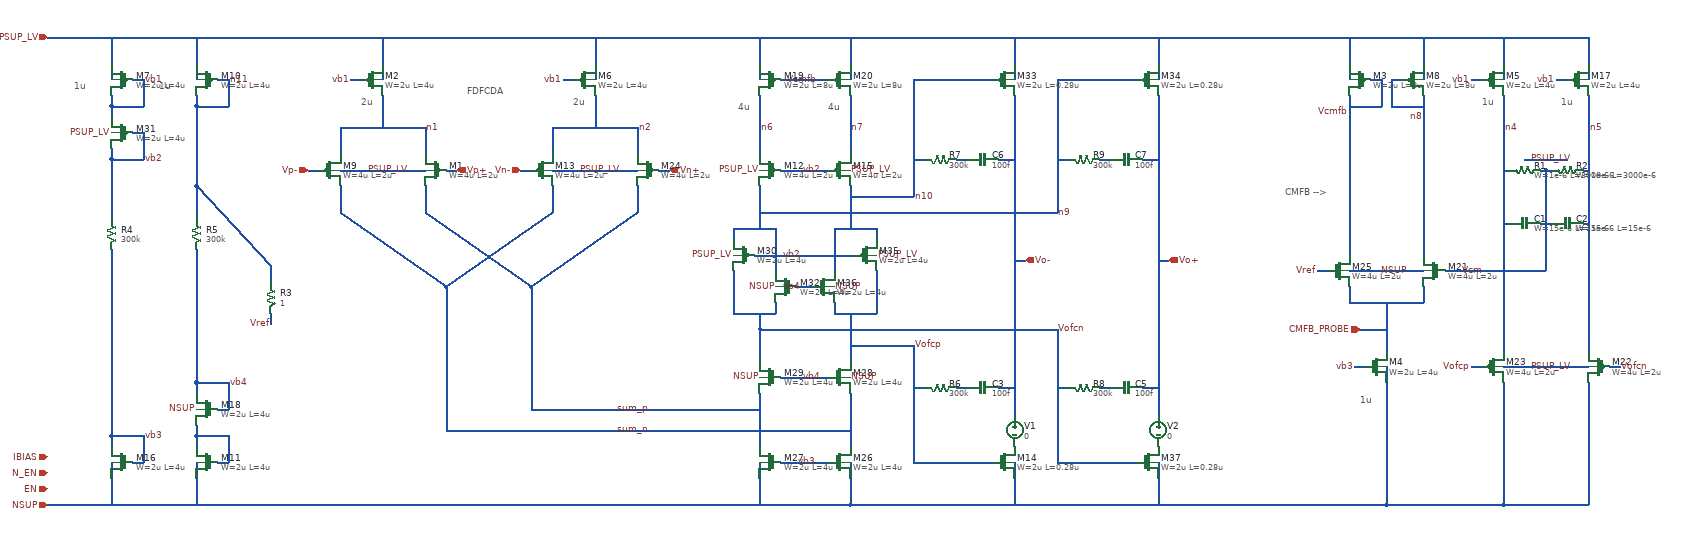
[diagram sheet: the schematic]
v {xschem version=3.4.7 file_version=1.2}
G {}
K {}
V {}
S {}
E {}
T {1u} -620 -650 0 0 0.4 0.4 {}
T {2u} -80 -620 0 0 0.4 0.4 {}
T {2u} 320 -620 0 0 0.4 0.4 {}
T {CMFB -->} 1660 -450 0 0 0.4 0.4 {}
T {4u} 630 -610 0 0 0.4 0.4 {}
T {4u} 800 -610 0 0 0.4 0.4 {}
T {1u} 1800 -60 0 0 0.4 0.4 {}
T {FDFCDA} 120 -640 0 0 0.4 0.4 {}
T {1u} 2030 -620 0 0 0.4 0.4 {}
T {1u} 2180 -620 0 0 0.4 0.4 {}
T {1u} -460 -650 0 0 0.4 0.4 {}
N -660 -730 -260 -730 {lab=PSUP_LV}
N -670 -730 -660 -730 {lab=PSUP_LV}
N -550 -680 -550 -650 {lab=PSUP_LV}
N -550 -730 -550 -680 {lab=PSUP_LV}
N -550 -600 -490 -600 {lab=vb1}
N -490 20 -490 70 {lab=vb3}
N -550 20 -550 40 {lab=vb3}
N -510 70 -490 70 {lab=vb3}
N -670 150 -230 150 {lab=NSUP}
N -120 -560 -120 -510 {lab=n1}
N 40 -560 40 -510 {lab=n1}
N -40 -620 -40 -560 {lab=n1}
N -40 -730 -40 -680 {lab=PSUP_LV}
N -120 -450 -120 -400 {lab=sum_n}
N 360 -680 360 -650 {lab=PSUP_LV}
N -100 -650 -80 -650 {lab=vb1}
N 300 -650 320 -650 {lab=vb1}
N 80 -480 100 -480 {lab=Vp+}
N -180 -480 -160 -480 {lab=Vp-}
N 1720 -290 1740 -290 {lab=Vref}
N 360 -730 360 -680 {lab=PSUP_LV}
N -40 -680 -40 -650 {lab=PSUP_LV}
N -120 -560 30 -560 {lab=n1}
N 280 -560 280 -510 {lab=n2}
N 440 -560 440 -510 {lab=n2}
N 280 -560 440 -560 {lab=n2}
N 360 -620 360 -560 {lab=n2}
N 40 -450 40 -400 {lab=sum_p}
N 440 -450 440 -400 {lab=sum_p}
N 220 -480 240 -480 {lab=Vn-}
N 480 -480 500 -480 {lab=Vn+}
N 30 -560 40 -560 {lab=n1}
N -120 -400 80 -260 {lab=sum_n}
N 80 -260 280 -400 {lab=sum_n}
N 280 -480 430 -480 {lab=PSUP_LV}
N 280 -450 280 -400 {lab=sum_n}
N 40 -400 240 -260 {lab=sum_p}
N 240 -260 440 -400 {lab=sum_p}
N 430 -480 440 -480 {lab=PSUP_LV}
N -510 -650 -490 -650 {lab=vb1}
N 710 -650 800 -650 {lab=Vcmfb}
N 710 70 800 70 {lab=vb3}
N 670 -620 670 -510 {lab=n6}
N 670 -730 670 -650 {lab=PSUP_LV}
N 840 -730 840 -650 {lab=PSUP_LV}
N 840 -620 840 -510 {lab=n7}
N -490 -650 -490 -600 {lab=vb1}
N -550 -620 -550 -600 {lab=vb1}
N -550 -500 -490 -500 {lab=vb2}
N -490 -550 -490 -500 {lab=vb2}
N -550 -520 -550 -500 {lab=vb2}
N -510 -550 -490 -550 {lab=vb2}
N -550 -600 -550 -580 {lab=vb1}
N -550 -500 -550 -450 {lab=vb2}
N 740 -90 760 -90 {lab=vb4}
N 710 -90 740 -90 {lab=vb4}
N 760 -90 800 -90 {lab=vb4}
N 740 -480 760 -480 {lab=vb2}
N 710 -480 740 -480 {lab=vb2}
N 760 -480 800 -480 {lab=vb2}
N 80 -100 80 -50 {lab=sum_n}
N 30 -730 1520 -730 {lab=PSUP_LV}
N 140 10 840 10 {lab=sum_n}
N 240 -30 610 -30 {lab=sum_p}
N 1780 -260 1780 -230 {lab=CMFB_PROBE}
N 1920 -260 1920 -230 {lab=CMFB_PROBE}
N 1780 -440 1780 -350 {lab=Vcmfb
}
N 1920 -400 1920 -350 {lab=n8}
N 1920 -460 1920 -400 {lab=n8}
N 1850 -80 1850 -20 {lab=NSUP}
N 1850 -110 1850 -80 {lab=NSUP}
N 1920 -330 1920 -320 {lab=n8}
N 1780 -330 1780 -320 {lab=Vcmfb}
N 1790 -290 1910 -290 {lab=NSUP}
N 1790 -230 1910 -230 {lab=CMFB_PROBE}
N 1820 -650 1830 -650 {lab=Vcmfb}
N 1780 -600 1830 -600 {lab=Vcmfb}
N 1870 -650 1880 -650 {lab=n8}
N 1870 -600 1920 -600 {lab=n8}
N 1830 -650 1840 -650 {lab=Vcmfb}
N 1840 -650 1840 -600 {lab=Vcmfb}
N 1830 -600 1840 -600 {lab=Vcmfb}
N 1860 -650 1870 -650 {lab=n8}
N 1860 -650 1860 -600 {lab=n8}
N 1860 -600 1870 -600 {lab=n8}
N 1780 -290 1790 -290 {lab=NSUP}
N 1910 -290 1920 -290 {lab=NSUP}
N 1780 -230 1790 -230 {lab=CMFB_PROBE}
N 1910 -230 1920 -230 {lab=CMFB_PROBE}
N 1920 -610 1920 -460 {lab=n8}
N 1780 -610 1780 -470 {lab=Vcmfb}
N 1780 -470 1780 -440 {lab=Vcmfb}
N 1920 -730 1920 -650 {lab=PSUP_LV}
N 1780 -730 1780 -650 {lab=PSUP_LV}
N 1780 -620 1780 -610 {lab=Vcmfb}
N 1920 -620 1920 -610 {lab=n8}
N 1790 -110 1810 -110 {lab=vb3}
N 1780 -350 1780 -330 {lab=Vcmfb}
N 1920 -350 1920 -330 {lab=n8}
N 1850 -230 1850 -140 {lab=CMFB_PROBE}
N 2010 -110 2030 -110 {lab=Vofcp}
N 2010 -110 2030 -110 {lab=Vofcp}
N 2270 -110 2290 -110 {lab=Vofcn}
N 2010 -650 2030 -650 {lab=vb1}
N 2010 -650 2030 -650 {lab=vb1}
N 2070 -620 2070 -140 {lab=n4}
N 2070 -80 2070 0 {lab=NSUP}
N 2070 -730 2070 -680 {lab=PSUP_LV}
N 2230 -620 2230 -140 {lab=n5}
N 2230 -80 2230 0 {lab=NSUP}
N 2230 -730 2230 -680 {lab=PSUP_LV}
N 2080 -110 2220 -110 {lab=PSUP_LV}
N 2150 -480 2160 -480 {lab=Vcm}
N 2140 -480 2150 -480 {lab=Vcm}
N 2150 -480 2150 -460 {lab=Vcm}
N 2110 -500 2150 -500 {lab=PSUP_LV}
N 2150 -500 2190 -500 {lab=PSUP_LV}
N 2070 -110 2080 -110 {lab=PSUP_LV}
N 2220 -110 2230 -110 {lab=PSUP_LV}
N 2070 -480 2080 -480 {lab=n4}
N 2220 -480 2230 -480 {lab=n5}
N 2070 -680 2070 -650 {lab=PSUP_LV}
N 2230 -680 2230 -650 {lab=PSUP_LV}
N 2170 -650 2190 -650 {lab=vb1}
N 2170 -650 2190 -650 {lab=vb1}
N 1960 -290 2150 -290 {lab=Vcm}
N 2150 -460 2150 -290 {lab=Vcm}
N 1850 -730 2230 -730 {lab=PSUP_LV}
N -250 -210 -250 -190 {lab=Vref}
N -260 -730 -10 -730 {lab=PSUP_LV}
N 1800 -180 1850 -180 {lab=CMFB_PROBE}
N 2070 -380 2080 -380 {lab=n4}
N 2140 -380 2150 -380 {lab=Vcm}
N 2150 -380 2160 -380 {lab=Vcm}
N 2220 -380 2230 -380 {lab=n5}
N -120 -480 40 -480 {lab=PSUP_LV}
N 610 -30 670 -30 {lab=sum_p}
N -550 -230 -550 -140 {lab=vb3}
N -550 20 -490 20 {lab=vb3}
N -550 -450 -550 -390 {lab=vb2}
N -550 -330 -550 -240 {lab=vb3}
N 240 -100 240 -60 {lab=sum_p}
N 80 10 140 10 {lab=sum_n}
N 80 -20 80 10 {lab=sum_n}
N -390 -680 -390 -650 {lab=PSUP_LV}
N -390 -730 -390 -680 {lab=PSUP_LV}
N -390 -600 -330 -600 {lab=n11}
N -330 20 -330 70 {lab=#net1}
N -390 20 -390 40 {lab=#net1}
N -350 70 -330 70 {lab=#net1}
N -350 -650 -330 -650 {lab=n11}
N -330 -650 -330 -600 {lab=n11}
N -390 -620 -390 -600 {lab=n11}
N -390 -600 -390 -580 {lab=n11}
N -390 20 -330 20 {lab=#net1}
N -390 -450 -390 -390 {lab=n11}
N -330 -80 -330 -30 {lab=vb4}
N -390 -80 -390 -60 {lab=vb4}
N -350 -30 -330 -30 {lab=vb4}
N -390 -80 -330 -80 {lab=vb4}
N -390 -330 -390 -280 {lab=vb4}
N -390 -580 -390 -450 {lab=n11}
N 620 -290 620 -210 {lab=Vofcn}
N 700 -220 700 -210 {lab=Vofcn}
N 700 -230 700 -220 {lab=Vofcn}
N 700 -360 700 -290 {lab=n9}
N 700 -370 700 -360 {lab=n9}
N 640 -370 700 -370 {lab=n9}
N 620 -370 620 -350 {lab=n9}
N 620 -370 640 -370 {lab=n9}
N 620 -210 640 -210 {lab=Vofcn}
N 740 -260 770 -260 {lab=vb4}
N 890 -290 890 -210 {lab=Vofcp}
N 810 -210 870 -210 {lab=Vofcp}
N 810 -220 810 -210 {lab=Vofcp}
N 810 -230 810 -220 {lab=Vofcp}
N 810 -360 810 -290 {lab=n10}
N 810 -370 810 -360 {lab=n10}
N 810 -370 870 -370 {lab=n10}
N 890 -370 890 -350 {lab=n10}
N 870 -370 890 -370 {lab=n10}
N 870 -210 890 -210 {lab=Vofcp}
N 640 -210 700 -210 {lab=Vofcn}
N 1520 -730 1850 -730 {lab=PSUP_LV}
N -550 -140 -550 0 {lab=vb3}
N 80 -250 80 -100 {lab=sum_n}
N 240 -250 240 -100 {lab=sum_p}
N 670 -450 670 -420 {lab=n9}
N 840 -450 840 -420 {lab=n10}
N 670 -200 670 -180 {lab=Vofcn}
N 660 -320 850 -320 {lab=vb2}
N -390 0 -390 20 {lab=#net1}
N -390 -270 -390 -100 {lab=vb4}
N -230 150 840 150 {lab=NSUP}
N 670 -380 670 -370 {lab=n9}
N 840 -380 840 -370 {lab=n10}
N 880 150 1850 150 {lab=NSUP}
N 1850 -20 1850 140 {lab=NSUP}
N 1850 150 2070 150 {lab=NSUP}
N 2070 0 2070 140 {lab=NSUP}
N 2070 150 2230 150 {lab=NSUP}
N 2230 0 2230 140 {lab=NSUP}
N 1150 -730 1150 -650 {lab=PSUP_LV}
N 1420 -730 1420 -650 {lab=PSUP_LV}
N 1150 70 1150 100 {lab=NSUP}
N 1420 70 1420 100 {lab=NSUP}
N 1150 -610 1150 -20 {lab=Vo-}
N 1420 -590 1420 -20 {lab=Vo+}
N 670 -180 670 -160 {lab=Vofcn}
N 670 -420 670 -380 {lab=n9}
N 840 -420 840 -380 {lab=n10}
N 840 -430 960 -430 {lab=n10}
N 960 -650 960 -430 {lab=n10}
N 1000 -650 1110 -650 {lab=n10}
N 1230 -650 1230 -430 {lab=n9}
N 1270 -650 1380 -650 {lab=n9}
N 1230 -430 1230 -400 {lab=n9}
N -390 -100 -390 -80 {lab=vb4}
N -550 0 -550 20 {lab=vb3}
N -390 100 -390 150 {lab=NSUP}
N -550 100 -550 150 {lab=NSUP}
N 840 100 840 150 {lab=NSUP}
N 840 70 840 100 {lab=NSUP}
N 670 70 670 150 {lab=NSUP}
N 670 20 670 40 {lab=sum_p}
N 840 20 840 40 {lab=sum_n}
N 240 -60 240 -40 {lab=sum_p}
N 80 -40 80 -20 {lab=sum_n}
N 670 -60 670 20 {lab=sum_p}
N 840 -60 840 20 {lab=sum_n}
N 670 -160 670 -120 {lab=Vofcn}
N 840 -160 840 -120 {lab=Vofcp}
N 1150 100 1150 150 {lab=NSUP}
N 1420 100 1420 150 {lab=NSUP}
N 1420 -620 1420 -600 {lab=Vo+}
N 80 -50 80 -40 {lab=sum_n}
N 240 -40 240 -30 {lab=sum_p}
N 840 -150 960 -150 {lab=Vofcp}
N 960 -150 960 70 {lab=Vofcp}
N 1000 70 1110 70 {lab=Vofcp}
N 670 -210 670 -200 {lab=Vofcn}
N 240 -260 240 -250 {lab=sum_p}
N 80 -260 80 -250 {lab=sum_n}
N -550 -240 -550 -230 {lab=vb3}
N -390 -280 -390 -270 {lab=vb4}
N 1850 140 1850 150 {lab=NSUP}
N 2070 140 2070 150 {lab=NSUP}
N 2230 140 2230 150 {lab=NSUP}
N 1230 -180 1230 40 {lab=Vofcn}
N 1230 40 1230 70 {lab=Vofcn}
N 1270 70 1380 70 {lab=Vofcn}
N 1420 -600 1420 -590 {lab=Vo+}
N 1150 -620 1150 -610 {lab=Vo-}
N -550 70 -550 100 {lab=NSUP}
N -390 70 -390 100 {lab=NSUP}
N 670 -400 910 -400 {lab=n9}
N 840 -210 840 -160 {lab=Vofcp}
N 670 -180 910 -180 {lab=Vofcn}
N 1040 -70 1060 -70 {lab=#net2}
N 840 150 880 150 {lab=NSUP}
N 960 70 1000 70 {lab=Vofcp}
N 910 -180 950 -180 {lab=Vofcn}
N 910 -400 950 -400 {lab=n9}
N 960 -650 1000 -650 {lab=n10}
N -10 -730 30 -730 {lab=PSUP_LV}
N 950 -400 1230 -400 {lab=n9}
N 950 -180 1230 -180 {lab=Vofcn}
N 1230 -650 1270 -650 {lab=n9}
N 1230 70 1270 70 {lab=Vofcn}
N 1120 -70 1150 -70 {lab=Vo-}
N 1230 -70 1250 -70 {lab=Vofcn}
N 1390 -70 1420 -70 {lab=Vo+}
N 1310 -70 1330 -70 {lab=#net3}
N 1040 -500 1060 -500 {lab=#net4}
N 960 -500 980 -500 {lab=n10}
N 1120 -500 1150 -500 {lab=Vo-}
N 1310 -500 1330 -500 {lab=#net5}
N 1230 -500 1250 -500 {lab=n9}
N 1390 -500 1420 -500 {lab=Vo+}
N 960 -70 980 -70 {lab=Vofcp}
N 1150 -310 1170 -310 {lab=Vo-}
N 1420 -310 1440 -310 {lab=Vo+}
N -250 -300 -250 -270 {lab=n11}
N -390 -450 -250 -300 {lab=n11}
C {noconn.sym} -670 90 0 1 {name=l1}
C {noconn.sym} -670 120 0 1 {name=l2}
C {ipin.sym} -670 -730 0 0 {name=p19 lab=PSUP_LV
}
C {ipin.sym} -670 150 0 0 {name=p20 lab=NSUP
}
C {ipin.sym} -670 90 0 0 {name=p21 lab=N_EN

}
C {ipin.sym} -670 120 0 0 {name=p22 lab=EN
}
C {ipin.sym} -670 60 0 0 {name=p9 lab=IBIAS


}
C {symbols/pfet_03v3.sym} -530 -650 0 1 {name=M7
L=4u
W=2u
nf=1
m=4
ad="'int((nf+1)/2) * W/nf * 0.18u'"
pd="'2*int((nf+1)/2) * (W/nf + 0.18u)'"
as="'int((nf+2)/2) * W/nf * 0.18u'"
ps="'2*int((nf+2)/2) * (W/nf + 0.18u)'"
nrd="'0.18u / W'" nrs="'0.18u / W'"
sa=0 sb=0 sd=0
model=pfet_03v3
spiceprefix=X
}
C {lab_pin.sym} -490 -650 0 1 {name=p8 sig_type=std_logic lab=vb1}
C {noconn.sym} -670 60 0 1 {name=l3}
C {symbols/nfet_03v3.sym} -530 70 0 1 {name=M16
L=4u
W=2u
nf=1
m=4
ad="'int((nf+1)/2) * W/nf * 0.18u'"
pd="'2*int((nf+1)/2) * (W/nf + 0.18u)'"
as="'int((nf+2)/2) * W/nf * 0.18u'"
ps="'2*int((nf+2)/2) * (W/nf + 0.18u)'"
nrd="'0.18u / W'" nrs="'0.18u / W'"
sa=0 sb=0 sd=0
model=nfet_03v3
spiceprefix=X
}
C {lab_pin.sym} -490 20 2 0 {name=p29 sig_type=std_logic lab=vb3}
C {symbols/pfet_03v3.sym} -140 -480 0 0 {name=M9
L=2u
W=4u
nf=5
m=20
ad="'int((nf+1)/2) * W/nf * 0.18u'"
pd="'2*int((nf+1)/2) * (W/nf + 0.18u)'"
as="'int((nf+2)/2) * W/nf * 0.18u'"
ps="'2*int((nf+2)/2) * (W/nf + 0.18u)'"
nrd="'0.18u / W'" nrs="'0.18u / W'"
sa=0 sb=0 sd=0
model=pfet_03v3
spiceprefix=X
}
C {symbols/pfet_03v3.sym} 60 -480 0 1 {name=M1
L=2u
W=4u
nf=5
m=20
ad="'int((nf+1)/2) * W/nf * 0.18u'"
pd="'2*int((nf+1)/2) * (W/nf + 0.18u)'"
as="'int((nf+2)/2) * W/nf * 0.18u'"
ps="'2*int((nf+2)/2) * (W/nf + 0.18u)'"
nrd="'0.18u / W'" nrs="'0.18u / W'"
sa=0 sb=0 sd=0
model=pfet_03v3
spiceprefix=X
}
C {lab_pin.sym} -70 -480 2 0 {name=p6 sig_type=std_logic lab=PSUP_LV}
C {symbols/pfet_03v3.sym} -60 -650 0 0 {name=M2
L=4u
W=2u
nf=1
m=8
ad="'int((nf+1)/2) * W/nf * 0.18u'"
pd="'2*int((nf+1)/2) * (W/nf + 0.18u)'"
as="'int((nf+2)/2) * W/nf * 0.18u'"
ps="'2*int((nf+2)/2) * (W/nf + 0.18u)'"
nrd="'0.18u / W'" nrs="'0.18u / W'"
sa=0 sb=0 sd=0
model=pfet_03v3
spiceprefix=X
}
C {symbols/pfet_03v3.sym} 340 -650 0 0 {name=M6
L=4u
W=2u
nf=1
m=8
ad="'int((nf+1)/2) * W/nf * 0.18u'"
pd="'2*int((nf+1)/2) * (W/nf + 0.18u)'"
as="'int((nf+2)/2) * W/nf * 0.18u'"
ps="'2*int((nf+2)/2) * (W/nf + 0.18u)'"
nrd="'0.18u / W'" nrs="'0.18u / W'"
sa=0 sb=0 sd=0
model=pfet_03v3
spiceprefix=X
}
C {lab_pin.sym} -100 -650 0 0 {name=p16 sig_type=std_logic lab=vb1}
C {lab_pin.sym} 300 -650 0 0 {name=p17 sig_type=std_logic lab=vb1}
C {ipin.sym} 100 -480 0 1 {name=p23 lab=Vp+

}
C {ipin.sym} -180 -480 0 0 {name=p24 lab=Vp-

}
C {ipin.sym} 500 -480 0 1 {name=p25 lab=Vn+

}
C {ipin.sym} 220 -480 0 0 {name=p26 lab=Vn-

}
C {lab_pin.sym} 1720 -290 0 0 {name=p7 sig_type=std_logic lab=Vref}
C {lab_pin.sym} 40 -560 2 0 {name=p11 sig_type=std_logic lab=n1}
C {lab_pin.sym} 440 -560 2 0 {name=p14 sig_type=std_logic lab=n2}
C {symbols/pfet_03v3.sym} 460 -480 0 1 {name=M24
L=2u
W=4u
nf=5
m=20
ad="'int((nf+1)/2) * W/nf * 0.18u'"
pd="'2*int((nf+1)/2) * (W/nf + 0.18u)'"
as="'int((nf+2)/2) * W/nf * 0.18u'"
ps="'2*int((nf+2)/2) * (W/nf + 0.18u)'"
nrd="'0.18u / W'" nrs="'0.18u / W'"
sa=0 sb=0 sd=0
model=pfet_03v3
spiceprefix=X
}
C {lab_pin.sym} 330 -480 2 0 {name=p28 sig_type=std_logic lab=PSUP_LV}
C {symbols/pfet_03v3.sym} 260 -480 0 0 {name=M13
L=2u
W=4u
nf=5
m=20
ad="'int((nf+1)/2) * W/nf * 0.18u'"
pd="'2*int((nf+1)/2) * (W/nf + 0.18u)'"
as="'int((nf+2)/2) * W/nf * 0.18u'"
ps="'2*int((nf+2)/2) * (W/nf + 0.18u)'"
nrd="'0.18u / W'" nrs="'0.18u / W'"
sa=0 sb=0 sd=0
model=pfet_03v3
spiceprefix=X
}
C {symbols/pfet_03v3.sym} 690 -480 0 1 {name=M12
L=2u
W=4u
nf=5
m=20
ad="'int((nf+1)/2) * W/nf * 0.18u'"
pd="'2*int((nf+1)/2) * (W/nf + 0.18u)'"
as="'int((nf+2)/2) * W/nf * 0.18u'"
ps="'2*int((nf+2)/2) * (W/nf + 0.18u)'"
nrd="'0.18u / W'" nrs="'0.18u / W'"
sa=0 sb=0 sd=0
model=pfet_03v3
spiceprefix=X
}
C {symbols/pfet_03v3.sym} 820 -480 0 0 {name=M15
L=2u
W=4u
nf=5
m=20
ad="'int((nf+1)/2) * W/nf * 0.18u'"
pd="'2*int((nf+1)/2) * (W/nf + 0.18u)'"
as="'int((nf+2)/2) * W/nf * 0.18u'"
ps="'2*int((nf+2)/2) * (W/nf + 0.18u)'"
nrd="'0.18u / W'" nrs="'0.18u / W'"
sa=0 sb=0 sd=0
model=pfet_03v3
spiceprefix=X
}
C {lab_pin.sym} 670 -480 2 1 {name=p34 sig_type=std_logic lab=PSUP_LV}
C {symbols/pfet_03v3.sym} 690 -650 0 1 {name=M19
L=8u
W=2u
nf=1
m=16
ad="'int((nf+1)/2) * W/nf * 0.18u'"
pd="'2*int((nf+1)/2) * (W/nf + 0.18u)'"
as="'int((nf+2)/2) * W/nf * 0.18u'"
ps="'2*int((nf+2)/2) * (W/nf + 0.18u)'"
nrd="'0.18u / W'" nrs="'0.18u / W'"
sa=0 sb=0 sd=0
model=pfet_03v3
spiceprefix=X
}
C {symbols/pfet_03v3.sym} 820 -650 0 0 {name=M20
L=8u
W=2u
nf=1
m=16
ad="'int((nf+1)/2) * W/nf * 0.18u'"
pd="'2*int((nf+1)/2) * (W/nf + 0.18u)'"
as="'int((nf+2)/2) * W/nf * 0.18u'"
ps="'2*int((nf+2)/2) * (W/nf + 0.18u)'"
nrd="'0.18u / W'" nrs="'0.18u / W'"
sa=0 sb=0 sd=0
model=pfet_03v3
spiceprefix=X
}
C {lab_pin.sym} 840 -480 2 0 {name=p37 sig_type=std_logic lab=PSUP_LV}
C {symbols/nfet_03v3.sym} 820 70 0 0 {name=M26
L=4u
W=2u
nf=1
m=16
ad="'int((nf+1)/2) * W/nf * 0.18u'"
pd="'2*int((nf+1)/2) * (W/nf + 0.18u)'"
as="'int((nf+2)/2) * W/nf * 0.18u'"
ps="'2*int((nf+2)/2) * (W/nf + 0.18u)'"
nrd="'0.18u / W'" nrs="'0.18u / W'"
sa=0 sb=0 sd=0
model=nfet_03v3
spiceprefix=X
}
C {lab_pin.sym} 780 -650 0 0 {name=p39 sig_type=std_logic lab=Vcmfb}
C {lab_pin.sym} 740 70 2 0 {name=p38 sig_type=std_logic lab=vb3}
C {symbols/nfet_03v3.sym} 690 70 0 1 {name=M27
L=4u
W=2u
nf=1
m=16
ad="'int((nf+1)/2) * W/nf * 0.18u'"
pd="'2*int((nf+1)/2) * (W/nf + 0.18u)'"
as="'int((nf+2)/2) * W/nf * 0.18u'"
ps="'2*int((nf+2)/2) * (W/nf + 0.18u)'"
nrd="'0.18u / W'" nrs="'0.18u / W'"
sa=0 sb=0 sd=0
model=nfet_03v3
spiceprefix=X
}
C {symbols/nfet_03v3.sym} 820 -90 0 0 {name=M28
L=4u
W=2u
nf=1
m=16
ad="'int((nf+1)/2) * W/nf * 0.18u'"
pd="'2*int((nf+1)/2) * (W/nf + 0.18u)'"
as="'int((nf+2)/2) * W/nf * 0.18u'"
ps="'2*int((nf+2)/2) * (W/nf + 0.18u)'"
nrd="'0.18u / W'" nrs="'0.18u / W'"
sa=0 sb=0 sd=0
model=nfet_03v3
spiceprefix=X
}
C {symbols/nfet_03v3.sym} 690 -90 0 1 {name=M29
L=4u
W=2u
nf=1
m=16
ad="'int((nf+1)/2) * W/nf * 0.18u'"
pd="'2*int((nf+1)/2) * (W/nf + 0.18u)'"
as="'int((nf+2)/2) * W/nf * 0.18u'"
ps="'2*int((nf+2)/2) * (W/nf + 0.18u)'"
nrd="'0.18u / W'" nrs="'0.18u / W'"
sa=0 sb=0 sd=0
model=nfet_03v3
spiceprefix=X
}
C {lab_pin.sym} 400 -30 2 0 {name=p41 sig_type=std_logic lab=sum_p}
C {lab_pin.sym} 400 10 2 0 {name=p43 sig_type=std_logic lab=sum_n}
C {symbols/pfet_03v3.sym} -530 -550 0 1 {name=M31
L=4u
W=2u
nf=1
m=4
ad="'int((nf+1)/2) * W/nf * 0.18u'"
pd="'2*int((nf+1)/2) * (W/nf + 0.18u)'"
as="'int((nf+2)/2) * W/nf * 0.18u'"
ps="'2*int((nf+2)/2) * (W/nf + 0.18u)'"
nrd="'0.18u / W'" nrs="'0.18u / W'"
sa=0 sb=0 sd=0
model=pfet_03v3
spiceprefix=X
}
C {lab_pin.sym} 670 -90 2 1 {name=p50 sig_type=std_logic lab=NSUP}
C {lab_pin.sym} 840 -90 2 0 {name=p51 sig_type=std_logic lab=NSUP}
C {lab_pin.sym} -550 -550 2 1 {name=p18 sig_type=std_logic lab=PSUP_LV}
C {symbols/pfet_03v3.sym} 1800 -650 0 1 {name=M3
L=8u
W=2u
nf=1
m=2
ad="'int((nf+1)/2) * W/nf * 0.18u'"
pd="'2*int((nf+1)/2) * (W/nf + 0.18u)'"
as="'int((nf+2)/2) * W/nf * 0.18u'"
ps="'2*int((nf+2)/2) * (W/nf + 0.18u)'"
nrd="'0.18u / W'" nrs="'0.18u / W'"
sa=0 sb=0 sd=0
model=pfet_03v3
spiceprefix=X
}
C {symbols/pfet_03v3.sym} 1900 -650 0 0 {name=M8
L=8u
W=2u
nf=1
m=2
ad="'int((nf+1)/2) * W/nf * 0.18u'"
pd="'2*int((nf+1)/2) * (W/nf + 0.18u)'"
as="'int((nf+2)/2) * W/nf * 0.18u'"
ps="'2*int((nf+2)/2) * (W/nf + 0.18u)'"
nrd="'0.18u / W'" nrs="'0.18u / W'"
sa=0 sb=0 sd=0
model=pfet_03v3
spiceprefix=X
}
C {lab_pin.sym} 1890 -290 0 0 {name=p52 sig_type=std_logic lab=NSUP}
C {symbols/nfet_03v3.sym} 1940 -290 0 1 {name=M21
L=2u
W=4u
nf=5
m=4
ad="'int((nf+1)/2) * W/nf * 0.18u'"
pd="'2*int((nf+1)/2) * (W/nf + 0.18u)'"
as="'int((nf+2)/2) * W/nf * 0.18u'"
ps="'2*int((nf+2)/2) * (W/nf + 0.18u)'"
nrd="'0.18u / W'" nrs="'0.18u / W'"
sa=0 sb=0 sd=0
model=nfet_03v3
spiceprefix=X
}
C {symbols/nfet_03v3.sym} 1760 -290 0 0 {name=M25
L=2u
W=4u
nf=5
m=4
ad="'int((nf+1)/2) * W/nf * 0.18u'"
pd="'2*int((nf+1)/2) * (W/nf + 0.18u)'"
as="'int((nf+2)/2) * W/nf * 0.18u'"
ps="'2*int((nf+2)/2) * (W/nf + 0.18u)'"
nrd="'0.18u / W'" nrs="'0.18u / W'"
sa=0 sb=0 sd=0
model=nfet_03v3
spiceprefix=X
}
C {lab_pin.sym} 1780 -590 0 0 {name=p1 sig_type=std_logic lab=Vcmfb}
C {lab_pin.sym} 1790 -110 0 0 {name=p12 sig_type=std_logic lab=vb3}
C {symbols/nfet_03v3.sym} 1830 -110 0 0 {name=M4
L=4u
W=2u
nf=1
m=4
ad="'int((nf+1)/2) * W/nf * 0.18u'"
pd="'2*int((nf+1)/2) * (W/nf + 0.18u)'"
as="'int((nf+2)/2) * W/nf * 0.18u'"
ps="'2*int((nf+2)/2) * (W/nf + 0.18u)'"
nrd="'0.18u / W'" nrs="'0.18u / W'"
sa=0 sb=0 sd=0
model=nfet_03v3
spiceprefix=X
}
C {lab_pin.sym} 670 -560 2 0 {name=p35 sig_type=std_logic lab=n6}
C {lab_pin.sym} 840 -560 2 0 {name=p36 sig_type=std_logic lab=n7}
C {symbols/pfet_03v3.sym} 2250 -110 0 1 {name=M22
L=2u
W=4u
nf=1
m=10
ad="'int((nf+1)/2) * W/nf * 0.18u'"
pd="'2*int((nf+1)/2) * (W/nf + 0.18u)'"
as="'int((nf+2)/2) * W/nf * 0.18u'"
ps="'2*int((nf+2)/2) * (W/nf + 0.18u)'"
nrd="'0.18u / W'" nrs="'0.18u / W'"
sa=0 sb=0 sd=0
model=pfet_03v3
spiceprefix=X
}
C {symbols/pfet_03v3.sym} 2050 -110 0 0 {name=M23
L=2u
W=4u
nf=1
m=10
ad="'int((nf+1)/2) * W/nf * 0.18u'"
pd="'2*int((nf+1)/2) * (W/nf + 0.18u)'"
as="'int((nf+2)/2) * W/nf * 0.18u'"
ps="'2*int((nf+2)/2) * (W/nf + 0.18u)'"
nrd="'0.18u / W'" nrs="'0.18u / W'"
sa=0 sb=0 sd=0
model=pfet_03v3
spiceprefix=X
}
C {symbols/ppolyf_u_3k.sym} 2110 -480 1 0 {name=R1
W=1e-6
L=3000e-6
model=ppolyf_u_3k
spiceprefix=X
m=1
}
C {symbols/ppolyf_u_3k.sym} 2190 -480 1 0 {name=R2
W=1e-6
L=3000e-6
model=ppolyf_u_3k
spiceprefix=X
m=1
}
C {lab_pin.sym} 1990 -290 0 1 {name=p46 sig_type=std_logic lab=Vcm}
C {lab_pin.sym} 2120 -500 0 1 {name=p53 sig_type=std_logic lab=PSUP_LV}
C {lab_pin.sym} 2070 -560 2 0 {name=p54 sig_type=std_logic lab=n4}
C {lab_pin.sym} 2230 -560 2 0 {name=p55 sig_type=std_logic lab=n5}
C {lab_pin.sym} 2120 -110 2 0 {name=p56 sig_type=std_logic lab=PSUP_LV}
C {symbols/pfet_03v3.sym} 2050 -650 0 0 {name=M5
L=4u
W=2u
nf=1
m=4
ad="'int((nf+1)/2) * W/nf * 0.18u'"
pd="'2*int((nf+1)/2) * (W/nf + 0.18u)'"
as="'int((nf+2)/2) * W/nf * 0.18u'"
ps="'2*int((nf+2)/2) * (W/nf + 0.18u)'"
nrd="'0.18u / W'" nrs="'0.18u / W'"
sa=0 sb=0 sd=0
model=pfet_03v3
spiceprefix=X
}
C {symbols/pfet_03v3.sym} 2210 -650 0 0 {name=M17
L=4u
W=2u
nf=1
m=4
ad="'int((nf+1)/2) * W/nf * 0.18u'"
pd="'2*int((nf+1)/2) * (W/nf + 0.18u)'"
as="'int((nf+2)/2) * W/nf * 0.18u'"
ps="'2*int((nf+2)/2) * (W/nf + 0.18u)'"
nrd="'0.18u / W'" nrs="'0.18u / W'"
sa=0 sb=0 sd=0
model=pfet_03v3
spiceprefix=X
}
C {lab_pin.sym} 2010 -650 0 0 {name=p57 sig_type=std_logic lab=vb1}
C {lab_pin.sym} 2170 -650 0 0 {name=p58 sig_type=std_logic lab=vb1}
C {lab_pin.sym} -250 -190 0 0 {name=p3 sig_type=std_logic lab=Vref}
C {res.sym} -250 -240 0 0 {name=R3
value=1
footprint=1206
device=resistor
m=1}
C {ipin.sym} 1800 -180 0 0 {name=p2 lab=CMFB_PROBE


}
C {gf180mcu_fd_pr/cap_mim_2f0fF.sym} 2110 -380 1 0 {name=C1
W=15e-6
L=15e-6
model=cap_mim_2f0fF
spiceprefix=X
m=1
}
C {gf180mcu_fd_pr/cap_mim_2f0fF.sym} 2190 -380 1 0 {name=C2
W=15e-6
L=15e-6
model=cap_mim_2f0fF
spiceprefix=X
m=1
}
C {lab_pin.sym} 750 -480 2 0 {name=p4 sig_type=std_logic lab=vb2}
C {lab_pin.sym} -490 -500 2 0 {name=p5 sig_type=std_logic lab=vb2}
C {res.sym} -550 -360 0 0 {name=R4
value=300k
footprint=1206
device=resistor
m=1}
C {lab_pin.sym} 1920 -580 0 0 {name=p10 sig_type=std_logic lab=n8}
C {symbols/pfet_03v3.sym} -370 -650 0 1 {name=M10
L=4u
W=2u
nf=1
m=4
ad="'int((nf+1)/2) * W/nf * 0.18u'"
pd="'2*int((nf+1)/2) * (W/nf + 0.18u)'"
as="'int((nf+2)/2) * W/nf * 0.18u'"
ps="'2*int((nf+2)/2) * (W/nf + 0.18u)'"
nrd="'0.18u / W'" nrs="'0.18u / W'"
sa=0 sb=0 sd=0
model=pfet_03v3
spiceprefix=X
}
C {symbols/nfet_03v3.sym} -370 70 0 1 {name=M11
L=4u
W=2u
nf=1
m=4
ad="'int((nf+1)/2) * W/nf * 0.18u'"
pd="'2*int((nf+1)/2) * (W/nf + 0.18u)'"
as="'int((nf+2)/2) * W/nf * 0.18u'"
ps="'2*int((nf+2)/2) * (W/nf + 0.18u)'"
nrd="'0.18u / W'" nrs="'0.18u / W'"
sa=0 sb=0 sd=0
model=nfet_03v3
spiceprefix=X
}
C {res.sym} -390 -360 0 0 {name=R5
value=300k
footprint=1206
device=resistor
m=1}
C {symbols/nfet_03v3.sym} -370 -30 0 1 {name=M18
L=4u
W=2u
nf=1
m=4
ad="'int((nf+1)/2) * W/nf * 0.18u'"
pd="'2*int((nf+1)/2) * (W/nf + 0.18u)'"
as="'int((nf+2)/2) * W/nf * 0.18u'"
ps="'2*int((nf+2)/2) * (W/nf + 0.18u)'"
nrd="'0.18u / W'" nrs="'0.18u / W'"
sa=0 sb=0 sd=0
model=nfet_03v3
spiceprefix=X
}
C {lab_pin.sym} -330 -80 2 0 {name=p33 sig_type=std_logic lab=vb4}
C {lab_pin.sym} -390 -30 0 0 {name=p32 sig_type=std_logic lab=NSUP}
C {lab_pin.sym} 750 -90 2 0 {name=p31 sig_type=std_logic lab=vb4}
C {lab_pin.sym} 620 -320 2 1 {name=p30 sig_type=std_logic lab=PSUP_LV}
C {lab_pin.sym} 700 -260 2 1 {name=p44 sig_type=std_logic lab=NSUP}
C {symbols/pfet_03v3.sym} 640 -320 0 1 {name=M30
L=4u
W=2u
nf=1
m=2
ad="'int((nf+1)/2) * W/nf * 0.18u'"
pd="'2*int((nf+1)/2) * (W/nf + 0.18u)'"
as="'int((nf+2)/2) * W/nf * 0.18u'"
ps="'2*int((nf+2)/2) * (W/nf + 0.18u)'"
nrd="'0.18u / W'" nrs="'0.18u / W'"
sa=0 sb=0 sd=0
model=pfet_03v3
spiceprefix=X
}
C {symbols/nfet_03v3.sym} 720 -260 0 1 {name=M32
L=4u
W=2u
nf=1
m=2
ad="'int((nf+1)/2) * W/nf * 0.18u'"
pd="'2*int((nf+1)/2) * (W/nf + 0.18u)'"
as="'int((nf+2)/2) * W/nf * 0.18u'"
ps="'2*int((nf+2)/2) * (W/nf + 0.18u)'"
nrd="'0.18u / W'" nrs="'0.18u / W'"
sa=0 sb=0 sd=0
model=nfet_03v3
spiceprefix=X
}
C {lab_pin.sym} 890 -320 2 0 {name=p59 sig_type=std_logic lab=PSUP_LV}
C {lab_pin.sym} 810 -260 2 0 {name=p60 sig_type=std_logic lab=NSUP}
C {symbols/pfet_03v3.sym} 870 -320 0 0 {name=M35
L=4u
W=2u
nf=1
m=2
ad="'int((nf+1)/2) * W/nf * 0.18u'"
pd="'2*int((nf+1)/2) * (W/nf + 0.18u)'"
as="'int((nf+2)/2) * W/nf * 0.18u'"
ps="'2*int((nf+2)/2) * (W/nf + 0.18u)'"
nrd="'0.18u / W'" nrs="'0.18u / W'"
sa=0 sb=0 sd=0
model=pfet_03v3
spiceprefix=X
}
C {symbols/nfet_03v3.sym} 790 -260 0 0 {name=M36
L=4u
W=2u
nf=1
m=2
ad="'int((nf+1)/2) * W/nf * 0.18u'"
pd="'2*int((nf+1)/2) * (W/nf + 0.18u)'"
as="'int((nf+2)/2) * W/nf * 0.18u'"
ps="'2*int((nf+2)/2) * (W/nf + 0.18u)'"
nrd="'0.18u / W'" nrs="'0.18u / W'"
sa=0 sb=0 sd=0
model=nfet_03v3
spiceprefix=X
}
C {lab_pin.sym} 750 -320 3 0 {name=p45 sig_type=std_logic lab=vb2}
C {lab_pin.sym} 750 -260 3 0 {name=p47 sig_type=std_logic lab=vb4}
C {symbols/nfet_03v3.sym} 1130 70 0 0 {name=M14
L=0.28u
W=2u
nf=4
m=4
ad="'int((nf+1)/2) * W/nf * 0.18u'"
pd="'2*int((nf+1)/2) * (W/nf + 0.18u)'"
as="'int((nf+2)/2) * W/nf * 0.18u'"
ps="'2*int((nf+2)/2) * (W/nf + 0.18u)'"
nrd="'0.18u / W'" nrs="'0.18u / W'"
sa=0 sb=0 sd=0
model=nfet_03v3
spiceprefix=X
}
C {symbols/nfet_03v3.sym} 1400 70 0 0 {name=M37
L=0.28u
W=2u
nf=4
m=4
ad="'int((nf+1)/2) * W/nf * 0.18u'"
pd="'2*int((nf+1)/2) * (W/nf + 0.18u)'"
as="'int((nf+2)/2) * W/nf * 0.18u'"
ps="'2*int((nf+2)/2) * (W/nf + 0.18u)'"
nrd="'0.18u / W'" nrs="'0.18u / W'"
sa=0 sb=0 sd=0
model=nfet_03v3
spiceprefix=X
}
C {vsource.sym} 1150 10 0 0 {name=V1 value=0 savecurrent=false}
C {vsource.sym} 1420 10 0 0 {name=V2 value=0 savecurrent=false}
C {symbols/pfet_03v3.sym} 1130 -650 0 0 {name=M33
L=0.28u
W=2u
nf=4
m=10
ad="'int((nf+1)/2) * W/nf * 0.18u'"
pd="'2*int((nf+1)/2) * (W/nf + 0.18u)'"
as="'int((nf+2)/2) * W/nf * 0.18u'"
ps="'2*int((nf+2)/2) * (W/nf + 0.18u)'"
nrd="'0.18u / W'" nrs="'0.18u / W'"
sa=0 sb=0 sd=0
model=pfet_03v3
spiceprefix=X
}
C {symbols/pfet_03v3.sym} 1400 -650 0 0 {name=M34
L=0.28u
W=2u
nf=4
m=10
ad="'int((nf+1)/2) * W/nf * 0.18u'"
pd="'2*int((nf+1)/2) * (W/nf + 0.18u)'"
as="'int((nf+2)/2) * W/nf * 0.18u'"
ps="'2*int((nf+2)/2) * (W/nf + 0.18u)'"
nrd="'0.18u / W'" nrs="'0.18u / W'"
sa=0 sb=0 sd=0
model=pfet_03v3
spiceprefix=X
}
C {opin.sym} 1440 -310 0 0 {name=p13 lab=Vo+
}
C {opin.sym} 1170 -310 0 0 {name=p27 lab=Vo-
}
C {lab_pin.sym} 2010 -110 2 1 {name=p15 sig_type=std_logic lab=Vofcp}
C {lab_pin.sym} 2290 -110 2 0 {name=p48 sig_type=std_logic lab=Vofcn}
C {lab_pin.sym} 1230 -400 0 1 {name=p40 sig_type=std_logic lab=n9}
C {lab_pin.sym} 960 -430 0 1 {name=p42 sig_type=std_logic lab=n10}
C {lab_pin.sym} -330 -650 2 0 {name=p49 sig_type=std_logic lab=n11}
C {capa.sym} 1090 -70 3 0 {name=C3
m=1
value=100f
footprint=1206
device="ceramic capacitor"
}
C {capa.sym} 1360 -70 3 0 {name=C5
m=1
value=100f
footprint=1206
device="ceramic capacitor"
}
C {capa.sym} 1090 -500 3 0 {name=C6
m=1
value=100f
footprint=1206
device="ceramic capacitor"
}
C {capa.sym} 1360 -500 3 0 {name=C7
m=1
value=100f
footprint=1206
device="ceramic capacitor"
}
C {res.sym} 1010 -500 1 0 {name=R7
value=300k
footprint=1206
device=resistor
m=1}
C {res.sym} 1280 -500 1 0 {name=R9
value=300k
footprint=1206
device=resistor
m=1}
C {res.sym} 1010 -70 1 0 {name=R6
value=300k
footprint=1206
device=resistor
m=1}
C {res.sym} 1280 -70 1 0 {name=R8
value=300k
footprint=1206
device=resistor
m=1}
C {lab_pin.sym} 960 -150 2 0 {name=p66 sig_type=std_logic lab=Vofcp}
C {lab_pin.sym} 1230 -180 2 0 {name=p67 sig_type=std_logic lab=Vofcn}
